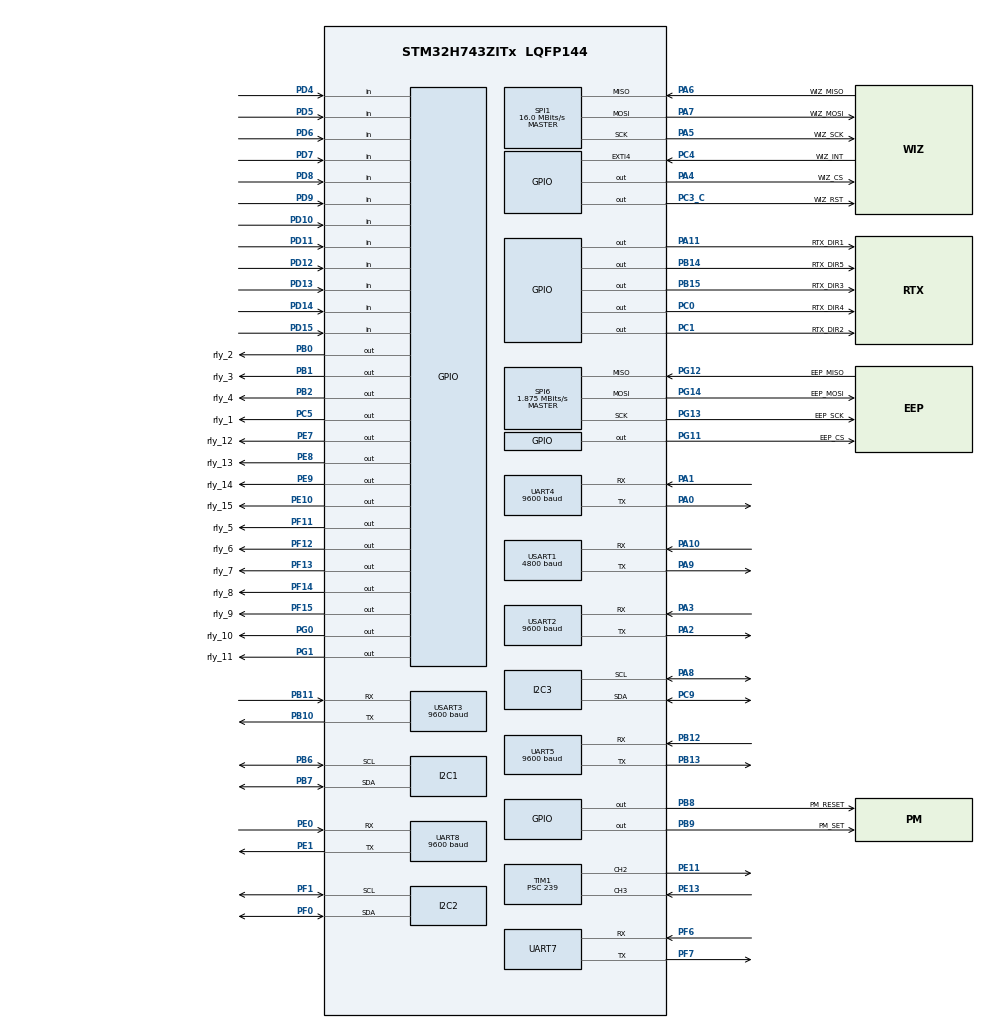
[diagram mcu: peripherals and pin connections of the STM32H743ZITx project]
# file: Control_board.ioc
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CORTEX_M7.default_mode_Activation=1
FREERTOS.Mutexes01=mqtt_mutex,Dynamic,NULL,Available
FREERTOS.Tasks01=StartMQTT,24,2048,StartMQTTTask,As weak,NULL,Dynamic,NULL,NULL;StartAppSensor,8,1024,StartAppSensorTask,As weak,NULL,Dynamic,NULL,NULL;StartAppTime,8,1024,StartAppTimeTask,As weak,NULL,Dynamic,NULL,NULL;PowerBoard,8,1024,PowerBoardTask,As weak,NULL,Dynamic,NULL,NULL;AP,8,1024,APTask,As weak,NULL,Dynamic,NULL,NULL;AC,8,1024,ACTask,As weak,NULL,Dynamic,NULL,NULL;FAN,8,1024,FANTask,As weak,NULL,Dynamic,NULL,NULL
FREERTOS.configTOTAL_HEAP_SIZE=49152
FREERTOS.configUSE_NEWLIB_REENTRANT=1
I2C1.Timing=0x307075B1
I2C2.Timing=0x307075B1
I2C3.I2C_Fall_Time=100
I2C3.I2C_Rise_Time=100
I2C3.Timing=0x30A175AB
Mcu.Family=STM32H7
Mcu.Name=STM32H743ZITx
Mcu.Package=LQFP144
NVIC.PriorityGroup=NVIC_PRIORITYGROUP_4
NVIC.TIM17_IRQn=true\:15\:0\:true\:false\:true\:false\:false\:true\:true
NVIC.TIM1_CC_IRQn=true\:5\:0\:false\:false\:true\:true\:true\:true\:true
NVIC.TIM1_TRG_COM_IRQn=true\:5\:0\:false\:false\:true\:true\:true\:true\:true
NVIC.TimeBase=TIM17_IRQn
NVIC.TimeBaseIP=TIM17
NVIC.UART4_IRQn=true\:5\:0\:false\:false\:true\:true\:true\:true\:true
NVIC.UART8_IRQn=true\:5\:0\:false\:false\:true\:true\:true\:true\:true
NVIC.USART3_IRQn=true\:5\:0\:false\:false\:true\:true\:true\:true\:true
PA0.Mode=Asynchronous
PA0.Signal=UART4_TX
PA1.Mode=Asynchronous
PA1.Signal=UART4_RX
PA10.Mode=Asynchronous
PA10.Signal=USART1_RX
PA11.GPIO_Label=RTX_DIR1
PA11.Signal=GPIO_Output
PA13\ (JTMS/SWDIO).Mode=Serial_Wire
PA13\ (JTMS/SWDIO).Signal=DEBUG_JTMS-SWDIO
PA14\ (JTCK/SWCLK).Mode=Serial_Wire
PA14\ (JTCK/SWCLK).Signal=DEBUG_JTCK-SWCLK
PA2.Mode=Asynchronous
PA2.Signal=USART2_TX
PA3.Mode=Asynchronous
PA3.Signal=USART2_RX
PA4.GPIO_Label=WIZ_CS
PA4.Signal=GPIO_Output
PA5.GPIO_Label=WIZ_SCK
PA5.Mode=Full_Duplex_Master
PA5.Signal=SPI1_SCK
PA6.GPIO_Label=WIZ_MISO
PA6.Mode=Full_Duplex_Master
PA6.Signal=SPI1_MISO
PA7.GPIO_Label=WIZ_MOSI
PA7.Mode=Full_Duplex_Master
PA7.Signal=SPI1_MOSI
PA8.Mode=I2C
PA8.Signal=I2C3_SCL
PA9.Mode=Asynchronous
PA9.Signal=USART1_TX
PB0.GPIO_Label=rly_2
PB0.Signal=GPIO_Output
PB1.GPIO_Label=rly_3
PB1.Signal=GPIO_Output
PB10.Mode=Asynchronous
PB10.Signal=USART3_TX
PB11.Mode=Asynchronous
PB11.Signal=USART3_RX
PB12.Mode=Asynchronous
PB12.Signal=UART5_RX
PB13.Mode=Asynchronous
PB13.Signal=UART5_TX
PB14.GPIO_Label=RTX_DIR5
PB14.Signal=GPIO_Output
PB15.GPIO_Label=RTX_DIR3
PB15.Signal=GPIO_Output
PB2.GPIO_Label=rly_4
PB2.Signal=GPIO_Output
PB6.Mode=I2C
PB6.Signal=I2C1_SCL
PB7.Mode=I2C
PB7.Signal=I2C1_SDA
PB8.GPIO_Label=PM_RESET
PB8.Signal=GPIO_Output
PB9.GPIO_Label=PM_SET
PB9.Signal=GPIO_Output
PC0.GPIO_Label=RTX_DIR4
PC0.Signal=GPIO_Output
PC1.GPIO_Label=RTX_DIR2
PC1.Signal=GPIO_Output
PC3_C.GPIO_Label=WIZ_RST
PC3_C.Signal=GPIO_Output
PC4.GPIO_Label=WIZ_INT
PC4.GPIO_ModeDefaultEXTI=GPIO_MODE_IT_FALLING
PC4.Signal=GPXTI4
PC5.GPIO_Label=rly_1
PC5.Signal=GPIO_Output
PC9.Mode=I2C
PC9.Signal=I2C3_SDA
PD10.Signal=GPIO_Input
PD11.Signal=GPIO_Input
PD12.Signal=GPIO_Input
PD13.GPIO_PuPd=GPIO_NOPULL
PD13.Signal=GPIO_Input
PD14.Signal=GPIO_Input
PD15.Signal=GPIO_Input
PD4.Signal=GPIO_Input
PD5.Signal=GPIO_Input
PD6.Signal=GPIO_Input
PD7.Signal=GPIO_Input
PD8.Signal=GPIO_Input
PD9.Signal=GPIO_Input
PE0.Mode=Asynchronous
PE0.Signal=UART8_RX
PE1.Mode=Asynchronous
PE1.Signal=UART8_TX
PE10.GPIO_Label=rly_15
PE10.Signal=GPIO_Output
PE11.Signal=S_TIM1_CH2
PE13.Signal=S_TIM1_CH3
PE7.GPIO_Label=rly_12
PE7.Signal=GPIO_Output
PE8.GPIO_Label=rly_13
PE8.Signal=GPIO_Output
PE9.GPIO_Label=rly_14
PE9.Signal=GPIO_Output
PF0.Mode=I2C
PF0.Signal=I2C2_SDA
PF1.Mode=I2C
PF1.Signal=I2C2_SCL
PF11.GPIO_Label=rly_5
PF11.Signal=GPIO_Output
PF12.GPIO_Label=rly_6
PF12.Signal=GPIO_Output
PF13.GPIO_Label=rly_7
PF13.Signal=GPIO_Output
PF14.GPIO_Label=rly_8
PF14.Signal=GPIO_Output
PF15.GPIO_Label=rly_9
PF15.Signal=GPIO_Output
PF6.Mode=Asynchronous
PF6.Signal=UART7_RX
PF7.Mode=Asynchronous
PF7.Signal=UART7_TX
PG0.GPIO_Label=rly_10
PG0.Signal=GPIO_Output
PG1.GPIO_Label=rly_11
PG1.Signal=GPIO_Output
PG11.GPIO_Label=EEP_CS
PG11.Signal=GPIO_Output
PG12.GPIO_Label=EEP_MISO
PG12.Mode=Full_Duplex_Master
PG12.Signal=SPI6_MISO
PG13.GPIO_Label=EEP_SCK
PG13.Mode=Full_Duplex_Master
PG13.Signal=SPI6_SCK
PG14.GPIO_Label=EEP_MOSI
PG14.Mode=Full_Duplex_Master
PG14.Signal=SPI6_MOSI
PH0-OSC_IN\ (PH0).Mode=HSE-External-Oscillator
PH0-OSC_IN\ (PH0).Signal=RCC_OSC_IN
PH1-OSC_OUT\ (PH1).Mode=HSE-External-Oscillator
PH1-OSC_OUT\ (PH1).Signal=RCC_OSC_OUT
ProjectManager.HeapSize=0x200
ProjectManager.StackSize=0x400
ProjectManager.TargetToolchain=STM32CubeIDE
RCC.ADCFreq_Value=32250000
RCC.APB1Freq_Value=120000000
RCC.APB2Freq_Value=120000000
RCC.APB3Freq_Value=120000000
RCC.APB4Freq_Value=120000000
RCC.CortexFreq_Value=480000000
RCC.D1PPRE=RCC_APB3_DIV2
RCC.D2PPRE1=RCC_APB1_DIV2
RCC.D2PPRE2=RCC_APB2_DIV2
RCC.D3PPRE=RCC_APB4_DIV2
RCC.DIVM1=1
RCC.DIVN1=60
RCC.HCLKFreq_Value=240000000
RCC.HPRE=RCC_HCLK_DIV2
RCC.HSE_VALUE=16000000
RCC.PLL2FRACN=0
RCC.PLL3FRACN=0
RCC.PLLFRACN=0
RCC.PLLSourceVirtual=RCC_PLLSOURCE_HSE
RCC.SPI123CLockSelection=RCC_SPI123CLKSOURCE_CLKP
RCC.SYSCLKFreq_VALUE=480000000
RCC.SYSCLKSource=RCC_SYSCLKSOURCE_PLLCLK
RCC.USBFreq_Value=480000000
SH.S_TIM1_CH2.0=TIM1_CH2,PWM Generation2 CH2
SH.S_TIM1_CH3.0=TIM1_CH3,Input_Capture3_from_TI3
SPI1.BaudRatePrescaler=SPI_BAUDRATEPRESCALER_4
SPI1.CalculateBaudRate=16.0 MBits/s
SPI1.DataSize=SPI_DATASIZE_8BIT
SPI1.Direction=SPI_DIRECTION_2LINES
SPI1.Mode=SPI_MODE_MASTER
SPI1.VirtualType=VM_MASTER
SPI6.BaudRatePrescaler=SPI_BAUDRATEPRESCALER_64
SPI6.CalculateBaudRate=1.875 MBits/s
SPI6.DataSize=SPI_DATASIZE_8BIT
SPI6.Direction=SPI_DIRECTION_2LINES
SPI6.Mode=SPI_MODE_MASTER
SPI6.NSSPMode=SPI_NSS_PULSE_DISABLE
SPI6.VirtualType=VM_MASTER
TIM1.AutoReloadPreload=TIM_AUTORELOAD_PRELOAD_ENABLE
TIM1.Channel-Input_Capture3_from_TI3=TIM_CHANNEL_3
TIM1.Channel-PWM\ Generation2\ CH2=TIM_CHANNEL_2
TIM1.ICFilter_CH3=10
TIM1.Period=999
TIM1.Prescaler=239
TIM1.Pulse-PWM\ Generation2\ CH2=500
UART4.BaudRate=9600
UART5.BaudRate=9600
UART8.BaudRate=9600
USART1.BaudRate=4800
USART1.VirtualMode-Asynchronous=VM_ASYNC
USART2.BaudRate=9600
USART2.VirtualMode-Asynchronous=VM_ASYNC
USART3.BaudRate=9600
USART3.VirtualMode-Asynchronous=VM_ASYNC
VP_FREERTOS_VS_CMSIS_V2.Mode=CMSIS_V2
VP_MEMORYMAP_VS_MEMORYMAP.Mode=CurAppReg
VP_RTC_VS_RTC_Activate.Mode=RTC_Enabled
VP_RTC_VS_RTC_Calendar.Mode=RTC_Calendar
VP_SYS_VS_tim17.Mode=TIM17
VP_TIM1_VS_ClockSourceINT.Mode=Internal
board=custom

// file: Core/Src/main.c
/* USER CODE BEGIN Header */
/**
  ******************************************************************************
  * @file           : main.c
  * @brief          : Main program body
  ******************************************************************************
  * @attention
  *
  * Copyright (c) 2026 STMicroelectronics.
  * All rights reserved.
  *
  * This software is licensed under terms that can be found in the LICENSE file
  * in the root directory of this software component.
  * If no LICENSE file comes with this software, it is provided AS-IS.
  *
  ******************************************************************************
  */
/* USER CODE END Header */
#include "main.h"
#include "cmsis_os.h"

I2C_HandleTypeDef hi2c1;
I2C_HandleTypeDef hi2c2;
I2C_HandleTypeDef hi2c3;

RTC_HandleTypeDef hrtc;

SPI_HandleTypeDef hspi1;
SPI_HandleTypeDef hspi6;

TIM_HandleTypeDef htim1;

UART_HandleTypeDef huart4;
UART_HandleTypeDef huart5;
UART_HandleTypeDef huart7;
UART_HandleTypeDef huart8;
UART_HandleTypeDef huart1;
UART_HandleTypeDef huart2;
UART_HandleTypeDef huart3;

/* Definitions for StartMQTT */
osThreadId_t StartMQTTHandle;
const osThreadAttr_t StartMQTT_attributes = {
  .name = "StartMQTT",
  .stack_size = 2048 * 4,
  .priority = (osPriority_t) osPriorityNormal,
};
/* Definitions for StartAppSensor */
osThreadId_t StartAppSensorHandle;
const osThreadAttr_t StartAppSensor_attributes = {
  .name = "StartAppSensor",
  .stack_size = 1024 * 4,
  .priority = (osPriority_t) osPriorityLow,
};
/* Definitions for StartAppTime */
osThreadId_t StartAppTimeHandle;
const osThreadAttr_t StartAppTime_attributes = {
  .name = "StartAppTime",
  .stack_size = 1024 * 4,
  .priority = (osPriority_t) osPriorityLow,
};
/* Definitions for PowerBoard */
osThreadId_t PowerBoardHandle;
const osThreadAttr_t PowerBoard_attributes = {
  .name = "PowerBoard",
  .stack_size = 1024 * 4,
  .priority = (osPriority_t) osPriorityLow,
};
/* Definitions for AP */
osThreadId_t APHandle;
const osThreadAttr_t AP_attributes = {
  .name = "AP",
  .stack_size = 1024 * 4,
  .priority = (osPriority_t) osPriorityLow,
};
/* Definitions for AC */
osThreadId_t ACHandle;
const osThreadAttr_t AC_attributes = {
  .name = "AC",
  .stack_size = 1024 * 4,
  .priority = (osPriority_t) osPriorityLow,
};
/* Definitions for FAN */
osThreadId_t FANHandle;
const osThreadAttr_t FAN_attributes = {
  .name = "FAN",
  .stack_size = 1024 * 4,
  .priority = (osPriority_t) osPriorityLow,
};
/* Definitions for mqtt_mutex */
osMutexId_t mqtt_mutexHandle;
const osMutexAttr_t mqtt_mutex_attributes = {
  .name = "mqtt_mutex"
};

void SystemClock_Config(void);
void PeriphCommonClock_Config(void);
static void MPU_Config(void);
static void MX_GPIO_Init(void);
static void MX_SPI1_Init(void);
static void MX_UART7_Init(void);
static void MX_I2C3_Init(void);
static void MX_UART8_Init(void);
static void MX_I2C2_Init(void);
static void MX_I2C1_Init(void);
static void MX_UART4_Init(void);
static void MX_UART5_Init(void);
static void MX_USART1_UART_Init(void);
static void MX_USART2_UART_Init(void);
static void MX_USART3_UART_Init(void);
static void MX_SPI6_Init(void);
static void MX_TIM1_Init(void);
static void MX_RTC_Init(void);
void StartMQTTTask(void *argument);
void StartAppSensorTask(void *argument);
void StartAppTimeTask(void *argument);
void PowerBoardTask(void *argument);
void APTask(void *argument);
void ACTask(void *argument);
void FANTask(void *argument);

/* USER CODE BEGIN PFP */
#ifdef __GNUC__
  /* With GCC, small printf (option LD Linker->Libraries->Small printf
	 set to 'Yes') calls __io_putchar() */
  #define PUTCHAR_PROTOTYPE int __io_putchar(int ch)
#else
  #define PUTCHAR_PROTOTYPE int fputc(int ch, FILE *f)
#endif /* __GNUC__ */
PUTCHAR_PROTOTYPE
{
	/* Place your implementation of fputc here */
	/* e.g. write a character to the EVAL_COM1 and Loop until the end of transmission */
	HAL_UART_Transmit(&huart7, (uint8_t *)&ch, 1, 0xFFFF);

	return ch;
}
/* USER CODE END PFP */

int main(void)
{

  /* MPU Configuration--------------------------------------------------------*/
  MPU_Config();

  /* MCU Configuration--------------------------------------------------------*/

  /* Reset of all peripherals, Initializes the Flash interface and the Systick. */
  HAL_Init();

  /* Configure the system clock */
  SystemClock_Config();

  /* Configure the peripherals common clocks */
  PeriphCommonClock_Config();

  /* Initialize all configured peripherals */
  MX_GPIO_Init();
  MX_SPI1_Init();
  MX_UART7_Init();
  MX_I2C3_Init();
  MX_UART8_Init();
  MX_I2C2_Init();
  MX_I2C1_Init();
  MX_UART4_Init();
  MX_UART5_Init();
  MX_USART1_UART_Init();
  MX_USART2_UART_Init();
  MX_USART3_UART_Init();
  MX_SPI6_Init();
  MX_TIM1_Init();
  MX_RTC_Init();

  /* Init scheduler */
  osKernelInitialize();
  /* Create the mutex(es) */
  /* creation of mqtt_mutex */
  mqtt_mutexHandle = osMutexNew(&mqtt_mutex_attributes);

  /* USER CODE BEGIN RTOS_QUEUES */
  /* add queues, ... */
#if 0
  /* USER CODE END RTOS_QUEUES */

  /* Create the thread(s) */
  /* creation of StartMQTT */
  StartMQTTHandle = osThreadNew(StartMQTTTask, NULL, &StartMQTT_attributes);

  /* creation of StartAppSensor */
  StartAppSensorHandle = osThreadNew(StartAppSensorTask, NULL, &StartAppSensor_attributes);

  /* creation of StartAppTime */
  StartAppTimeHandle = osThreadNew(StartAppTimeTask, NULL, &StartAppTime_attributes);

  /* creation of PowerBoard */
  PowerBoardHandle = osThreadNew(PowerBoardTask, NULL, &PowerBoard_attributes);

  /* creation of AP */
  APHandle = osThreadNew(APTask, NULL, &AP_attributes);

  /* creation of AC */
  ACHandle = osThreadNew(ACTask, NULL, &AC_attributes);

  /* creation of FAN */
  FANHandle = osThreadNew(FANTask, NULL, &FAN_attributes);

  /* USER CODE BEGIN RTOS_THREADS */
#endif
  /* add threads, ... */
  MX_App_Init();
  /* USER CODE END RTOS_THREADS */

  /* Start scheduler */
  osKernelStart();

  /* We should never get here as control is now taken by the scheduler */

  /* Infinite loop */
  while (1)
  {

  }
}

void SystemClock_Config(void)
{
  RCC_OscInitTypeDef RCC_OscInitStruct = {0};
  RCC_ClkInitTypeDef RCC_ClkInitStruct = {0};

  /** Supply configuration update enable
  */
  HAL_PWREx_ConfigSupply(PWR_LDO_SUPPLY);

  /** Configure the main internal regulator output voltage
  */
  __HAL_PWR_VOLTAGESCALING_CONFIG(PWR_REGULATOR_VOLTAGE_SCALE0);

  while(!__HAL_PWR_GET_FLAG(PWR_FLAG_VOSRDY)) {}

  /** Initializes the RCC Oscillators according to the specified parameters
  * in the RCC_OscInitTypeDef structure.
  */
  RCC_OscInitStruct.OscillatorType = RCC_OSCILLATORTYPE_HSI|RCC_OSCILLATORTYPE_LSI
                              |RCC_OSCILLATORTYPE_HSE;
  RCC_OscInitStruct.HSEState = RCC_HSE_ON;
  RCC_OscInitStruct.HSIState = RCC_HSI_DIV1;
  RCC_OscInitStruct.HSICalibrationValue = RCC_HSICALIBRATION_DEFAULT;
  RCC_OscInitStruct.LSIState = RCC_LSI_ON;
  RCC_OscInitStruct.PLL.PLLState = RCC_PLL_ON;
  RCC_OscInitStruct.PLL.PLLSource = RCC_PLLSOURCE_HSE;
  RCC_OscInitStruct.PLL.PLLM = 1;
  RCC_OscInitStruct.PLL.PLLN = 60;
  RCC_OscInitStruct.PLL.PLLP = 2;
  RCC_OscInitStruct.PLL.PLLQ = 2;
  RCC_OscInitStruct.PLL.PLLR = 2;
  RCC_OscInitStruct.PLL.PLLRGE = RCC_PLL1VCIRANGE_3;
  RCC_OscInitStruct.PLL.PLLVCOSEL = RCC_PLL1VCOWIDE;
  RCC_OscInitStruct.PLL.PLLFRACN = 0;
  if (HAL_RCC_OscConfig(&RCC_OscInitStruct) != HAL_OK)
  {
    Error_Handler();
  }

  /** Initializes the CPU, AHB and APB buses clocks
  */
  RCC_ClkInitStruct.ClockType = RCC_CLOCKTYPE_HCLK|RCC_CLOCKTYPE_SYSCLK
                              |RCC_CLOCKTYPE_PCLK1|RCC_CLOCKTYPE_PCLK2
                              |RCC_CLOCKTYPE_D3PCLK1|RCC_CLOCKTYPE_D1PCLK1;
  RCC_ClkInitStruct.SYSCLKSource = RCC_SYSCLKSOURCE_PLLCLK;
  RCC_ClkInitStruct.SYSCLKDivider = RCC_SYSCLK_DIV1;
  RCC_ClkInitStruct.AHBCLKDivider = RCC_HCLK_DIV2;
  RCC_ClkInitStruct.APB3CLKDivider = RCC_APB3_DIV2;
  RCC_ClkInitStruct.APB1CLKDivider = RCC_APB1_DIV2;
  RCC_ClkInitStruct.APB2CLKDivider = RCC_APB2_DIV2;
  RCC_ClkInitStruct.APB4CLKDivider = RCC_APB4_DIV2;

  if (HAL_RCC_ClockConfig(&RCC_ClkInitStruct, FLASH_LATENCY_4) != HAL_OK)
  {
    Error_Handler();
  }
}

void PeriphCommonClock_Config(void)
{
  RCC_PeriphCLKInitTypeDef PeriphClkInitStruct = {0};

  /** Initializes the peripherals clock
  */
  PeriphClkInitStruct.PeriphClockSelection = RCC_PERIPHCLK_CKPER;
  PeriphClkInitStruct.CkperClockSelection = RCC_CLKPSOURCE_HSI;
  if (HAL_RCCEx_PeriphCLKConfig(&PeriphClkInitStruct) != HAL_OK)
  {
    Error_Handler();
  }
}

static void MX_I2C1_Init(void)
{

  hi2c1.Instance = I2C1;
  hi2c1.Init.Timing = 0x307075B1;
  hi2c1.Init.OwnAddress1 = 0;
  hi2c1.Init.AddressingMode = I2C_ADDRESSINGMODE_7BIT;
  hi2c1.Init.DualAddressMode = I2C_DUALADDRESS_DISABLE;
  hi2c1.Init.OwnAddress2 = 0;
  hi2c1.Init.OwnAddress2Masks = I2C_OA2_NOMASK;
  hi2c1.Init.GeneralCallMode = I2C_GENERALCALL_DISABLE;
  hi2c1.Init.NoStretchMode = I2C_NOSTRETCH_DISABLE;
  if (HAL_I2C_Init(&hi2c1) != HAL_OK)
  {
    Error_Handler();
  }

  /** Configure Analogue filter
  */
  if (HAL_I2CEx_ConfigAnalogFilter(&hi2c1, I2C_ANALOGFILTER_ENABLE) != HAL_OK)
  {
    Error_Handler();
  }

  /** Configure Digital filter
  */
  if (HAL_I2CEx_ConfigDigitalFilter(&hi2c1, 0) != HAL_OK)
  {
    Error_Handler();
  }

}

static void MX_I2C2_Init(void)
{

  hi2c2.Instance = I2C2;
  hi2c2.Init.Timing = 0x307075B1;
  hi2c2.Init.OwnAddress1 = 0;
  hi2c2.Init.AddressingMode = I2C_ADDRESSINGMODE_7BIT;
  hi2c2.Init.DualAddressMode = I2C_DUALADDRESS_DISABLE;
  hi2c2.Init.OwnAddress2 = 0;
  hi2c2.Init.OwnAddress2Masks = I2C_OA2_NOMASK;
  hi2c2.Init.GeneralCallMode = I2C_GENERALCALL_DISABLE;
  hi2c2.Init.NoStretchMode = I2C_NOSTRETCH_DISABLE;
  if (HAL_I2C_Init(&hi2c2) != HAL_OK)
  {
    Error_Handler();
  }

  /** Configure Analogue filter
  */
  if (HAL_I2CEx_ConfigAnalogFilter(&hi2c2, I2C_ANALOGFILTER_ENABLE) != HAL_OK)
  {
    Error_Handler();
  }

  /** Configure Digital filter
  */
  if (HAL_I2CEx_ConfigDigitalFilter(&hi2c2, 0) != HAL_OK)
  {
    Error_Handler();
  }

}

static void MX_I2C3_Init(void)
{

  hi2c3.Instance = I2C3;
  hi2c3.Init.Timing = 0x30A175AB;
  hi2c3.Init.OwnAddress1 = 0;
  hi2c3.Init.AddressingMode = I2C_ADDRESSINGMODE_7BIT;
  hi2c3.Init.DualAddressMode = I2C_DUALADDRESS_DISABLE;
  hi2c3.Init.OwnAddress2 = 0;
  hi2c3.Init.OwnAddress2Masks = I2C_OA2_NOMASK;
  hi2c3.Init.GeneralCallMode = I2C_GENERALCALL_DISABLE;
  hi2c3.Init.NoStretchMode = I2C_NOSTRETCH_DISABLE;
  if (HAL_I2C_Init(&hi2c3) != HAL_OK)
  {
    Error_Handler();
  }

  /** Configure Analogue filter
  */
  if (HAL_I2CEx_ConfigAnalogFilter(&hi2c3, I2C_ANALOGFILTER_ENABLE) != HAL_OK)
  {
    Error_Handler();
  }

  /** Configure Digital filter
  */
  if (HAL_I2CEx_ConfigDigitalFilter(&hi2c3, 0) != HAL_OK)
  {
    Error_Handler();
  }

}

static void MX_RTC_Init(void)
{

  RTC_TimeTypeDef sTime = {0};
  RTC_DateTypeDef sDate = {0};

  /** Initialize RTC Only
  */
  hrtc.Instance = RTC;
  hrtc.Init.HourFormat = RTC_HOURFORMAT_24;
  hrtc.Init.AsynchPrediv = 127;
  hrtc.Init.SynchPrediv = 255;
  hrtc.Init.OutPut = RTC_OUTPUT_DISABLE;
  hrtc.Init.OutPutPolarity = RTC_OUTPUT_POLARITY_HIGH;
  hrtc.Init.OutPutType = RTC_OUTPUT_TYPE_OPENDRAIN;
  hrtc.Init.OutPutRemap = RTC_OUTPUT_REMAP_NONE;
  if (HAL_RTC_Init(&hrtc) != HAL_OK)
  {
    Error_Handler();
  }

  /** Initialize RTC and set the Time and Date
  */
  sTime.Hours = 0x0;
  sTime.Minutes = 0x0;
  sTime.Seconds = 0x0;
  sTime.DayLightSaving = RTC_DAYLIGHTSAVING_NONE;
  sTime.StoreOperation = RTC_STOREOPERATION_RESET;
  if (HAL_RTC_SetTime(&hrtc, &sTime, RTC_FORMAT_BCD) != HAL_OK)
  {
    Error_Handler();
  }
  sDate.WeekDay = RTC_WEEKDAY_MONDAY;
  sDate.Month = RTC_MONTH_JANUARY;
  sDate.Date = 0x1;
  sDate.Year = 0x0;

  if (HAL_RTC_SetDate(&hrtc, &sDate, RTC_FORMAT_BCD) != HAL_OK)
  {
    Error_Handler();
  }

}

static void MX_SPI1_Init(void)
{

  /* SPI1 parameter configuration*/
  hspi1.Instance = SPI1;
  hspi1.Init.Mode = SPI_MODE_MASTER;
  hspi1.Init.Direction = SPI_DIRECTION_2LINES;
  hspi1.Init.DataSize = SPI_DATASIZE_8BIT;
  hspi1.Init.CLKPolarity = SPI_POLARITY_LOW;
  hspi1.Init.CLKPhase = SPI_PHASE_1EDGE;
  hspi1.Init.NSS = SPI_NSS_SOFT;
  hspi1.Init.BaudRatePrescaler = SPI_BAUDRATEPRESCALER_4;
  hspi1.Init.FirstBit = SPI_FIRSTBIT_MSB;
  hspi1.Init.TIMode = SPI_TIMODE_DISABLE;
  hspi1.Init.CRCCalculation = SPI_CRCCALCULATION_DISABLE;
  hspi1.Init.CRCPolynomial = 0x0;
  hspi1.Init.NSSPMode = SPI_NSS_PULSE_ENABLE;
  hspi1.Init.NSSPolarity = SPI_NSS_POLARITY_LOW;
  hspi1.Init.FifoThreshold = SPI_FIFO_THRESHOLD_01DATA;
  hspi1.Init.TxCRCInitializationPattern = SPI_CRC_INITIALIZATION_ALL_ZERO_PATTERN;
  hspi1.Init.RxCRCInitializationPattern = SPI_CRC_INITIALIZATION_ALL_ZERO_PATTERN;
  hspi1.Init.MasterSSIdleness = SPI_MASTER_SS_IDLENESS_00CYCLE;
  hspi1.Init.MasterInterDataIdleness = SPI_MASTER_INTERDATA_IDLENESS_00CYCLE;
  hspi1.Init.MasterReceiverAutoSusp = SPI_MASTER_RX_AUTOSUSP_DISABLE;
  hspi1.Init.MasterKeepIOState = SPI_MASTER_KEEP_IO_STATE_DISABLE;
  hspi1.Init.IOSwap = SPI_IO_SWAP_DISABLE;
  if (HAL_SPI_Init(&hspi1) != HAL_OK)
  {
    Error_Handler();
  }

}

static void MX_SPI6_Init(void)
{

  /* SPI6 parameter configuration*/
  hspi6.Instance = SPI6;
  hspi6.Init.Mode = SPI_MODE_MASTER;
  hspi6.Init.Direction = SPI_DIRECTION_2LINES;
  hspi6.Init.DataSize = SPI_DATASIZE_8BIT;
  hspi6.Init.CLKPolarity = SPI_POLARITY_LOW;
  hspi6.Init.CLKPhase = SPI_PHASE_1EDGE;
  hspi6.Init.NSS = SPI_NSS_SOFT;
  hspi6.Init.BaudRatePrescaler = SPI_BAUDRATEPRESCALER_64;
  hspi6.Init.FirstBit = SPI_FIRSTBIT_MSB;
  hspi6.Init.TIMode = SPI_TIMODE_DISABLE;
  hspi6.Init.CRCCalculation = SPI_CRCCALCULATION_DISABLE;
  hspi6.Init.CRCPolynomial = 0x0;
  hspi6.Init.NSSPMode = SPI_NSS_PULSE_DISABLE;
  hspi6.Init.NSSPolarity = SPI_NSS_POLARITY_LOW;
  hspi6.Init.FifoThreshold = SPI_FIFO_THRESHOLD_01DATA;
  hspi6.Init.TxCRCInitializationPattern = SPI_CRC_INITIALIZATION_ALL_ZERO_PATTERN;
  hspi6.Init.RxCRCInitializationPattern = SPI_CRC_INITIALIZATION_ALL_ZERO_PATTERN;
  hspi6.Init.MasterSSIdleness = SPI_MASTER_SS_IDLENESS_00CYCLE;
  hspi6.Init.MasterInterDataIdleness = SPI_MASTER_INTERDATA_IDLENESS_00CYCLE;
  hspi6.Init.MasterReceiverAutoSusp = SPI_MASTER_RX_AUTOSUSP_DISABLE;
  hspi6.Init.MasterKeepIOState = SPI_MASTER_KEEP_IO_STATE_DISABLE;
  hspi6.Init.IOSwap = SPI_IO_SWAP_DISABLE;
  if (HAL_SPI_Init(&hspi6) != HAL_OK)
  {
    Error_Handler();
  }

}

static void MX_TIM1_Init(void)
{

  TIM_ClockConfigTypeDef sClockSourceConfig = {0};
  TIM_MasterConfigTypeDef sMasterConfig = {0};
  TIM_OC_InitTypeDef sConfigOC = {0};
  TIM_IC_InitTypeDef sConfigIC = {0};
  TIM_BreakDeadTimeConfigTypeDef sBreakDeadTimeConfig = {0};

  htim1.Instance = TIM1;
  htim1.Init.Prescaler = 239;
  htim1.Init.CounterMode = TIM_COUNTERMODE_UP;
  htim1.Init.Period = 999;
  htim1.Init.ClockDivision = TIM_CLOCKDIVISION_DIV1;
  htim1.Init.RepetitionCounter = 0;
  htim1.Init.AutoReloadPreload = TIM_AUTORELOAD_PRELOAD_ENABLE;
  if (HAL_TIM_Base_Init(&htim1) != HAL_OK)
  {
    Error_Handler();
  }
  sClockSourceConfig.ClockSource = TIM_CLOCKSOURCE_INTERNAL;
  if (HAL_TIM_ConfigClockSource(&htim1, &sClockSourceConfig) != HAL_OK)
  {
    Error_Handler();
  }
  if (HAL_TIM_PWM_Init(&htim1) != HAL_OK)
  {
    Error_Handler();
  }
  if (HAL_TIM_IC_Init(&htim1) != HAL_OK)
  {
    Error_Handler();
  }
  sMasterConfig.MasterOutputTrigger = TIM_TRGO_RESET;
  sMasterConfig.MasterOutputTrigger2 = TIM_TRGO2_RESET;
  sMasterConfig.MasterSlaveMode = TIM_MASTERSLAVEMODE_DISABLE;
  if (HAL_TIMEx_MasterConfigSynchronization(&htim1, &sMasterConfig) != HAL_OK)
  {
    Error_Handler();
  }
  sConfigOC.OCMode = TIM_OCMODE_PWM1;
  sConfigOC.Pulse = 500;
  sConfigOC.OCPolarity = TIM_OCPOLARITY_HIGH;
  sConfigOC.OCNPolarity = TIM_OCNPOLARITY_HIGH;
  sConfigOC.OCFastMode = TIM_OCFAST_DISABLE;
  sConfigOC.OCIdleState = TIM_OCIDLESTATE_RESET;
  sConfigOC.OCNIdleState = TIM_OCNIDLESTATE_RESET;
  if (HAL_TIM_PWM_ConfigChannel(&htim1, &sConfigOC, TIM_CHANNEL_2) != HAL_OK)
  {
    Error_Handler();
  }
  sConfigIC.ICPolarity = TIM_INPUTCHANNELPOLARITY_RISING;
  sConfigIC.ICSelection = TIM_ICSELECTION_DIRECTTI;
  sConfigIC.ICPrescaler = TIM_ICPSC_DIV1;
  sConfigIC.ICFilter = 10;
  if (HAL_TIM_IC_ConfigChannel(&htim1, &sConfigIC, TIM_CHANNEL_3) != HAL_OK)
  {
    Error_Handler();
  }
  sBreakDeadTimeConfig.OffStateRunMode = TIM_OSSR_DISABLE;
  sBreakDeadTimeConfig.OffStateIDLEMode = TIM_OSSI_DISABLE;
  sBreakDeadTimeConfig.LockLevel = TIM_LOCKLEVEL_OFF;
  sBreakDeadTimeConfig.DeadTime = 0;
  sBreakDeadTimeConfig.BreakState = TIM_BREAK_DISABLE;
  sBreakDeadTimeConfig.BreakPolarity = TIM_BREAKPOLARITY_HIGH;
  sBreakDeadTimeConfig.BreakFilter = 0;
  sBreakDeadTimeConfig.Break2State = TIM_BREAK2_DISABLE;
  sBreakDeadTimeConfig.Break2Polarity = TIM_BREAK2POLARITY_HIGH;
  sBreakDeadTimeConfig.Break2Filter = 0;
  sBreakDeadTimeConfig.AutomaticOutput = TIM_AUTOMATICOUTPUT_DISABLE;
  if (HAL_TIMEx_ConfigBreakDeadTime(&htim1, &sBreakDeadTimeConfig) != HAL_OK)
  {
    Error_Handler();
  }
  HAL_TIM_MspPostInit(&htim1);

}

static void MX_UART4_Init(void)
{

  huart4.Instance = UART4;
  huart4.Init.BaudRate = 9600;
  huart4.Init.WordLength = UART_WORDLENGTH_8B;
  huart4.Init.StopBits = UART_STOPBITS_1;
  huart4.Init.Parity = UART_PARITY_NONE;
  huart4.Init.Mode = UART_MODE_TX_RX;
  huart4.Init.HwFlowCtl = UART_HWCONTROL_NONE;
  huart4.Init.OverSampling = UART_OVERSAMPLING_16;
  huart4.Init.OneBitSampling = UART_ONE_BIT_SAMPLE_DISABLE;
  huart4.Init.ClockPrescaler = UART_PRESCALER_DIV1;
  huart4.AdvancedInit.AdvFeatureInit = UART_ADVFEATURE_NO_INIT;
  if (HAL_UART_Init(&huart4) != HAL_OK)
  {
    Error_Handler();
  }
  if (HAL_UARTEx_SetTxFifoThreshold(&huart4, UART_TXFIFO_THRESHOLD_1_8) != HAL_OK)
  {
    Error_Handler();
  }
  if (HAL_UARTEx_SetRxFifoThreshold(&huart4, UART_RXFIFO_THRESHOLD_1_8) != HAL_OK)
  {
    Error_Handler();
  }
  if (HAL_UARTEx_DisableFifoMode(&huart4) != HAL_OK)
  {
    Error_Handler();
  }

}

static void MX_UART5_Init(void)
{

  huart5.Instance = UART5;
  huart5.Init.BaudRate = 9600;
  huart5.Init.WordLength = UART_WORDLENGTH_8B;
  huart5.Init.StopBits = UART_STOPBITS_1;
  huart5.Init.Parity = UART_PARITY_NONE;
  huart5.Init.Mode = UART_MODE_TX_RX;
  huart5.Init.HwFlowCtl = UART_HWCONTROL_NONE;
  huart5.Init.OverSampling = UART_OVERSAMPLING_16;
  huart5.Init.OneBitSampling = UART_ONE_BIT_SAMPLE_DISABLE;
  huart5.Init.ClockPrescaler = UART_PRESCALER_DIV1;
  huart5.AdvancedInit.AdvFeatureInit = UART_ADVFEATURE_NO_INIT;
  if (HAL_UART_Init(&huart5) != HAL_OK)
  {
    Error_Handler();
  }
  if (HAL_UARTEx_SetTxFifoThreshold(&huart5, UART_TXFIFO_THRESHOLD_1_8) != HAL_OK)
  {
    Error_Handler();
  }
  if (HAL_UARTEx_SetRxFifoThreshold(&huart5, UART_RXFIFO_THRESHOLD_1_8) != HAL_OK)
  {
    Error_Handler();
  }
  if (HAL_UARTEx_DisableFifoMode(&huart5) != HAL_OK)
  {
    Error_Handler();
  }

}

static void MX_UART7_Init(void)
{

  huart7.Instance = UART7;
  huart7.Init.BaudRate = 115200;
  huart7.Init.WordLength = UART_WORDLENGTH_8B;
  huart7.Init.StopBits = UART_STOPBITS_1;
  huart7.Init.Parity = UART_PARITY_NONE;
  huart7.Init.Mode = UART_MODE_TX_RX;
  huart7.Init.HwFlowCtl = UART_HWCONTROL_NONE;
  huart7.Init.OverSampling = UART_OVERSAMPLING_16;
  huart7.Init.OneBitSampling = UART_ONE_BIT_SAMPLE_DISABLE;
  huart7.Init.ClockPrescaler = UART_PRESCALER_DIV1;
  huart7.AdvancedInit.AdvFeatureInit = UART_ADVFEATURE_NO_INIT;
  if (HAL_UART_Init(&huart7) != HAL_OK)
  {
    Error_Handler();
  }
  if (HAL_UARTEx_SetTxFifoThreshold(&huart7, UART_TXFIFO_THRESHOLD_1_8) != HAL_OK)
  {
    Error_Handler();
  }
  if (HAL_UARTEx_SetRxFifoThreshold(&huart7, UART_RXFIFO_THRESHOLD_1_8) != HAL_OK)
  {
    Error_Handler();
  }
  if (HAL_UARTEx_DisableFifoMode(&huart7) != HAL_OK)
  {
    Error_Handler();
  }

}

static void MX_UART8_Init(void)
{

  huart8.Instance = UART8;
  huart8.Init.BaudRate = 9600;
  huart8.Init.WordLength = UART_WORDLENGTH_8B;
  huart8.Init.StopBits = UART_STOPBITS_1;
  huart8.Init.Parity = UART_PARITY_NONE;
  huart8.Init.Mode = UART_MODE_TX_RX;
  huart8.Init.HwFlowCtl = UART_HWCONTROL_NONE;
  huart8.Init.OverSampling = UART_OVERSAMPLING_16;
  huart8.Init.OneBitSampling = UART_ONE_BIT_SAMPLE_DISABLE;
  huart8.Init.ClockPrescaler = UART_PRESCALER_DIV1;
  huart8.AdvancedInit.AdvFeatureInit = UART_ADVFEATURE_NO_INIT;
  if (HAL_UART_Init(&huart8) != HAL_OK)
  {
    Error_Handler();
  }
  if (HAL_UARTEx_SetTxFifoThreshold(&huart8, UART_TXFIFO_THRESHOLD_1_8) != HAL_OK)
  {
    Error_Handler();
  }
  if (HAL_UARTEx_SetRxFifoThreshold(&huart8, UART_RXFIFO_THRESHOLD_1_8) != HAL_OK)
  {
    Error_Handler();
  }
  if (HAL_UARTEx_DisableFifoMode(&huart8) != HAL_OK)
  {
    Error_Handler();
  }

}

static void MX_USART1_UART_Init(void)
{

  huart1.Instance = USART1;
  huart1.Init.BaudRate = 4800;
  huart1.Init.WordLength = UART_WORDLENGTH_8B;
  huart1.Init.StopBits = UART_STOPBITS_1;
  huart1.Init.Parity = UART_PARITY_NONE;
  huart1.Init.Mode = UART_MODE_TX_RX;
  huart1.Init.HwFlowCtl = UART_HWCONTROL_NONE;
  huart1.Init.OverSampling = UART_OVERSAMPLING_16;
  huart1.Init.OneBitSampling = UART_ONE_BIT_SAMPLE_DISABLE;
  huart1.Init.ClockPrescaler = UART_PRESCALER_DIV1;
  huart1.AdvancedInit.AdvFeatureInit = UART_ADVFEATURE_NO_INIT;
  if (HAL_UART_Init(&huart1) != HAL_OK)
  {
    Error_Handler();
  }
  if (HAL_UARTEx_SetTxFifoThreshold(&huart1, UART_TXFIFO_THRESHOLD_1_8) != HAL_OK)
  {
    Error_Handler();
  }
  if (HAL_UARTEx_SetRxFifoThreshold(&huart1, UART_RXFIFO_THRESHOLD_1_8) != HAL_OK)
  {
    Error_Handler();
  }
  if (HAL_UARTEx_DisableFifoMode(&huart1) != HAL_OK)
  {
    Error_Handler();
  }

}

static void MX_USART2_UART_Init(void)
{

  huart2.Instance = USART2;
  huart2.Init.BaudRate = 9600;
  huart2.Init.WordLength = UART_WORDLENGTH_8B;
  huart2.Init.StopBits = UART_STOPBITS_1;
  huart2.Init.Parity = UART_PARITY_NONE;
  huart2.Init.Mode = UART_MODE_TX_RX;
  huart2.Init.HwFlowCtl = UART_HWCONTROL_NONE;
  huart2.Init.OverSampling = UART_OVERSAMPLING_16;
  huart2.Init.OneBitSampling = UART_ONE_BIT_SAMPLE_DISABLE;
  huart2.Init.ClockPrescaler = UART_PRESCALER_DIV1;
  huart2.AdvancedInit.AdvFeatureInit = UART_ADVFEATURE_NO_INIT;
  if (HAL_UART_Init(&huart2) != HAL_OK)
  {
    Error_Handler();
  }
  if (HAL_UARTEx_SetTxFifoThreshold(&huart2, UART_TXFIFO_THRESHOLD_1_8) != HAL_OK)
  {
    Error_Handler();
  }
  if (HAL_UARTEx_SetRxFifoThreshold(&huart2, UART_RXFIFO_THRESHOLD_1_8) != HAL_OK)
  {
    Error_Handler();
  }
  if (HAL_UARTEx_DisableFifoMode(&huart2) != HAL_OK)
  {
    Error_Handler();
  }

}

static void MX_USART3_UART_Init(void)
{

  huart3.Instance = USART3;
  huart3.Init.BaudRate = 9600;
  huart3.Init.WordLength = UART_WORDLENGTH_8B;
  huart3.Init.StopBits = UART_STOPBITS_1;
  huart3.Init.Parity = UART_PARITY_NONE;
  huart3.Init.Mode = UART_MODE_TX_RX;
  huart3.Init.HwFlowCtl = UART_HWCONTROL_NONE;
  huart3.Init.OverSampling = UART_OVERSAMPLING_16;
  huart3.Init.OneBitSampling = UART_ONE_BIT_SAMPLE_DISABLE;
  huart3.Init.ClockPrescaler = UART_PRESCALER_DIV1;
  huart3.AdvancedInit.AdvFeatureInit = UART_ADVFEATURE_NO_INIT;
  if (HAL_UART_Init(&huart3) != HAL_OK)
  {
    Error_Handler();
  }
  if (HAL_UARTEx_SetTxFifoThreshold(&huart3, UART_TXFIFO_THRESHOLD_1_8) != HAL_OK)
  {
    Error_Handler();
  }
  if (HAL_UARTEx_SetRxFifoThreshold(&huart3, UART_RXFIFO_THRESHOLD_1_8) != HAL_OK)
  {
    Error_Handler();
  }
  if (HAL_UARTEx_DisableFifoMode(&huart3) != HAL_OK)
  {
    Error_Handler();
  }

}

static void MX_GPIO_Init(void)
{
  GPIO_InitTypeDef GPIO_InitStruct = {0};

  /* GPIO Ports Clock Enable */
  __HAL_RCC_GPIOF_CLK_ENABLE();
  __HAL_RCC_GPIOH_CLK_ENABLE();
  __HAL_RCC_GPIOC_CLK_ENABLE();
  __HAL_RCC_GPIOA_CLK_ENABLE();
  __HAL_RCC_GPIOB_CLK_ENABLE();
  __HAL_RCC_GPIOG_CLK_ENABLE();
  __HAL_RCC_GPIOE_CLK_ENABLE();
  __HAL_RCC_GPIOD_CLK_ENABLE();

  /*Configure GPIO pin Output Level */
  HAL_GPIO_WritePin(GPIOC, RTX_DIR4_Pin|RTX_DIR2_Pin|WIZ_RST_Pin|rly_1_Pin, GPIO_PIN_RESET);

  /*Configure GPIO pin Output Level */
  HAL_GPIO_WritePin(GPIOA, WIZ_CS_Pin|RTX_DIR1_Pin, GPIO_PIN_RESET);

  /*Configure GPIO pin Output Level */
  HAL_GPIO_WritePin(GPIOB, rly_2_Pin|rly_3_Pin|rly_4_Pin|RTX_DIR5_Pin
                          |RTX_DIR3_Pin|PM_RESET_Pin|PM_SET_Pin, GPIO_PIN_RESET);

  /*Configure GPIO pin Output Level */
  HAL_GPIO_WritePin(GPIOF, rly_5_Pin|rly_6_Pin|rly_7_Pin|rly_8_Pin
                          |rly_9_Pin, GPIO_PIN_RESET);

  /*Configure GPIO pin Output Level */
  HAL_GPIO_WritePin(GPIOG, rly_10_Pin|rly_11_Pin|EEP_CS_Pin, GPIO_PIN_RESET);

  /*Configure GPIO pin Output Level */
  HAL_GPIO_WritePin(GPIOE, rly_12_Pin|rly_13_Pin|rly_14_Pin|rly_15_Pin, GPIO_PIN_RESET);

  /*Configure GPIO pins : RTX_DIR4_Pin RTX_DIR2_Pin WIZ_RST_Pin rly_1_Pin */
  GPIO_InitStruct.Pin = RTX_DIR4_Pin|RTX_DIR2_Pin|WIZ_RST_Pin|rly_1_Pin;
  GPIO_InitStruct.Mode = GPIO_MODE_OUTPUT_PP;
  GPIO_InitStruct.Pull = GPIO_NOPULL;
  GPIO_InitStruct.Speed = GPIO_SPEED_FREQ_LOW;
  HAL_GPIO_Init(GPIOC, &GPIO_InitStruct);

  /*Configure GPIO pins : WIZ_CS_Pin RTX_DIR1_Pin */
  GPIO_InitStruct.Pin = WIZ_CS_Pin|RTX_DIR1_Pin;
  GPIO_InitStruct.Mode = GPIO_MODE_OUTPUT_PP;
  GPIO_InitStruct.Pull = GPIO_NOPULL;
  GPIO_InitStruct.Speed = GPIO_SPEED_FREQ_LOW;
  HAL_GPIO_Init(GPIOA, &GPIO_InitStruct);

  /*Configure GPIO pin : WIZ_INT_Pin */
  GPIO_InitStruct.Pin = WIZ_INT_Pin;
  GPIO_InitStruct.Mode = GPIO_MODE_IT_FALLING;
  GPIO_InitStruct.Pull = GPIO_NOPULL;
  HAL_GPIO_Init(WIZ_INT_GPIO_Port, &GPIO_InitStruct);

  /*Configure GPIO pins : rly_2_Pin rly_3_Pin rly_4_Pin RTX_DIR5_Pin
                           RTX_DIR3_Pin PM_RESET_Pin PM_SET_Pin */
  GPIO_InitStruct.Pin = rly_2_Pin|rly_3_Pin|rly_4_Pin|RTX_DIR5_Pin
                          |RTX_DIR3_Pin|PM_RESET_Pin|PM_SET_Pin;
  GPIO_InitStruct.Mode = GPIO_MODE_OUTPUT_PP;
  GPIO_InitStruct.Pull = GPIO_NOPULL;
  GPIO_InitStruct.Speed = GPIO_SPEED_FREQ_LOW;
  HAL_GPIO_Init(GPIOB, &GPIO_InitStruct);

  /*Configure GPIO pins : rly_5_Pin rly_6_Pin rly_7_Pin rly_8_Pin
                           rly_9_Pin */
  GPIO_InitStruct.Pin = rly_5_Pin|rly_6_Pin|rly_7_Pin|rly_8_Pin
                          |rly_9_Pin;
  GPIO_InitStruct.Mode = GPIO_MODE_OUTPUT_PP;
  GPIO_InitStruct.Pull = GPIO_NOPULL;
  GPIO_InitStruct.Speed = GPIO_SPEED_FREQ_LOW;
  HAL_GPIO_Init(GPIOF, &GPIO_InitStruct);

  /*Configure GPIO pins : rly_10_Pin rly_11_Pin EEP_CS_Pin */
  GPIO_InitStruct.Pin = rly_10_Pin|rly_11_Pin|EEP_CS_Pin;
  GPIO_InitStruct.Mode = GPIO_MODE_OUTPUT_PP;
  GPIO_InitStruct.Pull = GPIO_NOPULL;
  GPIO_InitStruct.Speed = GPIO_SPEED_FREQ_LOW;
  HAL_GPIO_Init(GPIOG, &GPIO_InitStruct);

  /*Configure GPIO pins : rly_12_Pin rly_13_Pin rly_14_Pin rly_15_Pin */
  GPIO_InitStruct.Pin = rly_12_Pin|rly_13_Pin|rly_14_Pin|rly_15_Pin;
  GPIO_InitStruct.Mode = GPIO_MODE_OUTPUT_PP;
  GPIO_InitStruct.Pull = GPIO_NOPULL;
  GPIO_InitStruct.Speed = GPIO_SPEED_FREQ_LOW;
  HAL_GPIO_Init(GPIOE, &GPIO_InitStruct);

  /*Configure GPIO pins : SW1_Pin SW2_Pin SW3_Pin SW4_Pin
                           SW5_Pin SW6_Pin SW7_Pin SW8_Pin
                           PD4 PD5 PD6 PD7 */
  GPIO_InitStruct.Pin = SW1_Pin|SW2_Pin|SW3_Pin|SW4_Pin
                          |SW5_Pin|SW6_Pin|SW7_Pin|SW8_Pin
                          |GPIO_PIN_4|GPIO_PIN_5|GPIO_PIN_6|GPIO_PIN_7;
  GPIO_InitStruct.Mode = GPIO_MODE_INPUT;
  GPIO_InitStruct.Pull = GPIO_NOPULL;
  HAL_GPIO_Init(GPIOD, &GPIO_InitStruct);

  /*AnalogSwitch Config */
  HAL_SYSCFG_AnalogSwitchConfig(SYSCFG_SWITCH_PC3, SYSCFG_SWITCH_PC3_CLOSE);

}

__weak void StartMQTTTask(void *argument)
{
  for(;;)
  {
    osDelay(1);
  }
}

__weak void StartAppSensorTask(void *argument)
{
  for(;;)
  {
    osDelay(1);
  }
}

__weak void StartAppTimeTask(void *argument)
{
  for(;;)
  {
    osDelay(1);
  }
}

__weak void PowerBoardTask(void *argument)
{
  for(;;)
  {
    osDelay(1);
  }
}

__weak void APTask(void *argument)
{
  for(;;)
  {
    osDelay(1);
  }
}

__weak void ACTask(void *argument)
{
  for(;;)
  {
    osDelay(1);
  }
}

__weak void FANTask(void *argument)
{
  for(;;)
  {
    osDelay(1);
  }
}

 /* MPU Configuration */

void MPU_Config(void)
{
  MPU_Region_InitTypeDef MPU_InitStruct = {0};

  /* Disables the MPU */
  HAL_MPU_Disable();

  /** Initializes and configures the Region and the memory to be protected
  */
  MPU_InitStruct.Enable = MPU_REGION_ENABLE;
  MPU_InitStruct.Number = MPU_REGION_NUMBER0;
  MPU_InitStruct.BaseAddress = 0x0;
  MPU_InitStruct.Size = MPU_REGION_SIZE_4GB;
  MPU_InitStruct.SubRegionDisable = 0x87;
  MPU_InitStruct.TypeExtField = MPU_TEX_LEVEL0;
  MPU_InitStruct.AccessPermission = MPU_REGION_NO_ACCESS;
  MPU_InitStruct.DisableExec = MPU_INSTRUCTION_ACCESS_DISABLE;
  MPU_InitStruct.IsShareable = MPU_ACCESS_SHAREABLE;
  MPU_InitStruct.IsCacheable = MPU_ACCESS_NOT_CACHEABLE;
  MPU_InitStruct.IsBufferable = MPU_ACCESS_NOT_BUFFERABLE;

  HAL_MPU_ConfigRegion(&MPU_InitStruct);
  /* Enables the MPU */
  HAL_MPU_Enable(MPU_PRIVILEGED_DEFAULT);

}

void HAL_TIM_PeriodElapsedCallback(TIM_HandleTypeDef *htim)
{
  if (htim->Instance == TIM17)
  {
    HAL_IncTick();
  }
}

void Error_Handler(void)
{
  __disable_irq();
  while (1)
  {
  }
}
